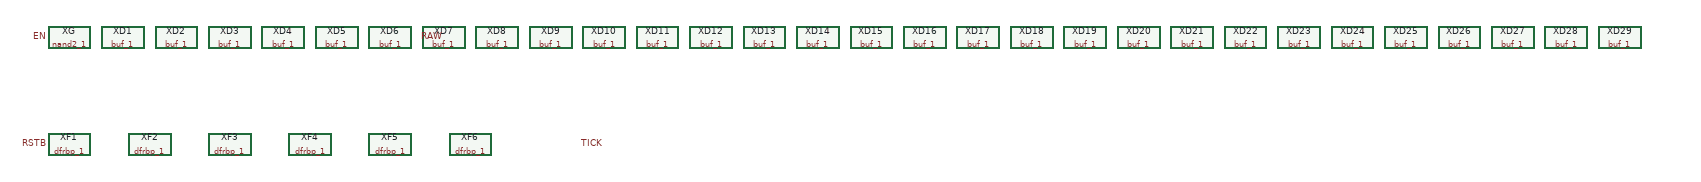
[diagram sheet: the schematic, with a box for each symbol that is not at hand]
v {xschem version=3.4.7 file_version=1.2
* watchdog ring + divider (generated)
}
G {}
K {}
V {}
S {}
E {}
C {sky130_stdcells/nand2_1.sym} 0 0 0 0 {name=XG VGND=GND VNB=GND VPB=VDD VPWR=VDD prefix=sky130_fd_sc_hd__}
C {sky130_stdcells/buf_1.sym} 100 0 0 0 {name=XD1 VGND=GND VNB=GND VPB=VDD VPWR=VDD prefix=sky130_fd_sc_hd__}
C {sky130_stdcells/buf_1.sym} 200 0 0 0 {name=XD2 VGND=GND VNB=GND VPB=VDD VPWR=VDD prefix=sky130_fd_sc_hd__}
C {sky130_stdcells/buf_1.sym} 300 0 0 0 {name=XD3 VGND=GND VNB=GND VPB=VDD VPWR=VDD prefix=sky130_fd_sc_hd__}
C {sky130_stdcells/buf_1.sym} 400 0 0 0 {name=XD4 VGND=GND VNB=GND VPB=VDD VPWR=VDD prefix=sky130_fd_sc_hd__}
C {sky130_stdcells/buf_1.sym} 500 0 0 0 {name=XD5 VGND=GND VNB=GND VPB=VDD VPWR=VDD prefix=sky130_fd_sc_hd__}
C {sky130_stdcells/buf_1.sym} 600 0 0 0 {name=XD6 VGND=GND VNB=GND VPB=VDD VPWR=VDD prefix=sky130_fd_sc_hd__}
C {sky130_stdcells/buf_1.sym} 700 0 0 0 {name=XD7 VGND=GND VNB=GND VPB=VDD VPWR=VDD prefix=sky130_fd_sc_hd__}
C {sky130_stdcells/buf_1.sym} 800 0 0 0 {name=XD8 VGND=GND VNB=GND VPB=VDD VPWR=VDD prefix=sky130_fd_sc_hd__}
C {sky130_stdcells/buf_1.sym} 900 0 0 0 {name=XD9 VGND=GND VNB=GND VPB=VDD VPWR=VDD prefix=sky130_fd_sc_hd__}
C {sky130_stdcells/buf_1.sym} 1000 0 0 0 {name=XD10 VGND=GND VNB=GND VPB=VDD VPWR=VDD prefix=sky130_fd_sc_hd__}
C {sky130_stdcells/buf_1.sym} 1100 0 0 0 {name=XD11 VGND=GND VNB=GND VPB=VDD VPWR=VDD prefix=sky130_fd_sc_hd__}
C {sky130_stdcells/buf_1.sym} 1200 0 0 0 {name=XD12 VGND=GND VNB=GND VPB=VDD VPWR=VDD prefix=sky130_fd_sc_hd__}
C {sky130_stdcells/buf_1.sym} 1300 0 0 0 {name=XD13 VGND=GND VNB=GND VPB=VDD VPWR=VDD prefix=sky130_fd_sc_hd__}
C {sky130_stdcells/buf_1.sym} 1400 0 0 0 {name=XD14 VGND=GND VNB=GND VPB=VDD VPWR=VDD prefix=sky130_fd_sc_hd__}
C {sky130_stdcells/buf_1.sym} 1500 0 0 0 {name=XD15 VGND=GND VNB=GND VPB=VDD VPWR=VDD prefix=sky130_fd_sc_hd__}
C {sky130_stdcells/buf_1.sym} 1600 0 0 0 {name=XD16 VGND=GND VNB=GND VPB=VDD VPWR=VDD prefix=sky130_fd_sc_hd__}
C {sky130_stdcells/buf_1.sym} 1700 0 0 0 {name=XD17 VGND=GND VNB=GND VPB=VDD VPWR=VDD prefix=sky130_fd_sc_hd__}
C {sky130_stdcells/buf_1.sym} 1800 0 0 0 {name=XD18 VGND=GND VNB=GND VPB=VDD VPWR=VDD prefix=sky130_fd_sc_hd__}
C {sky130_stdcells/buf_1.sym} 1900 0 0 0 {name=XD19 VGND=GND VNB=GND VPB=VDD VPWR=VDD prefix=sky130_fd_sc_hd__}
C {sky130_stdcells/buf_1.sym} 2000 0 0 0 {name=XD20 VGND=GND VNB=GND VPB=VDD VPWR=VDD prefix=sky130_fd_sc_hd__}
C {sky130_stdcells/buf_1.sym} 2100 0 0 0 {name=XD21 VGND=GND VNB=GND VPB=VDD VPWR=VDD prefix=sky130_fd_sc_hd__}
C {sky130_stdcells/buf_1.sym} 2200 0 0 0 {name=XD22 VGND=GND VNB=GND VPB=VDD VPWR=VDD prefix=sky130_fd_sc_hd__}
C {sky130_stdcells/buf_1.sym} 2300 0 0 0 {name=XD23 VGND=GND VNB=GND VPB=VDD VPWR=VDD prefix=sky130_fd_sc_hd__}
C {sky130_stdcells/buf_1.sym} 2400 0 0 0 {name=XD24 VGND=GND VNB=GND VPB=VDD VPWR=VDD prefix=sky130_fd_sc_hd__}
C {sky130_stdcells/buf_1.sym} 2500 0 0 0 {name=XD25 VGND=GND VNB=GND VPB=VDD VPWR=VDD prefix=sky130_fd_sc_hd__}
C {sky130_stdcells/buf_1.sym} 2600 0 0 0 {name=XD26 VGND=GND VNB=GND VPB=VDD VPWR=VDD prefix=sky130_fd_sc_hd__}
C {sky130_stdcells/buf_1.sym} 2700 0 0 0 {name=XD27 VGND=GND VNB=GND VPB=VDD VPWR=VDD prefix=sky130_fd_sc_hd__}
C {sky130_stdcells/buf_1.sym} 2800 0 0 0 {name=XD28 VGND=GND VNB=GND VPB=VDD VPWR=VDD prefix=sky130_fd_sc_hd__}
C {sky130_stdcells/buf_1.sym} 2900 0 0 0 {name=XD29 VGND=GND VNB=GND VPB=VDD VPWR=VDD prefix=sky130_fd_sc_hd__}
C {sky130_stdcells/dfrbp_1.sym} 0 200 0 0 {name=XF1 VGND=GND VNB=GND VPB=VDD VPWR=VDD prefix=sky130_fd_sc_hd__}
C {sky130_stdcells/dfrbp_1.sym} 150 200 0 0 {name=XF2 VGND=GND VNB=GND VPB=VDD VPWR=VDD prefix=sky130_fd_sc_hd__}
C {sky130_stdcells/dfrbp_1.sym} 300 200 0 0 {name=XF3 VGND=GND VNB=GND VPB=VDD VPWR=VDD prefix=sky130_fd_sc_hd__}
C {sky130_stdcells/dfrbp_1.sym} 450 200 0 0 {name=XF4 VGND=GND VNB=GND VPB=VDD VPWR=VDD prefix=sky130_fd_sc_hd__}
C {sky130_stdcells/dfrbp_1.sym} 600 200 0 0 {name=XF5 VGND=GND VNB=GND VPB=VDD VPWR=VDD prefix=sky130_fd_sc_hd__}
C {sky130_stdcells/dfrbp_1.sym} 750 200 0 0 {name=XF6 VGND=GND VNB=GND VPB=VDD VPWR=VDD prefix=sky130_fd_sc_hd__}
C {devices/lab_pin.sym} -40 0 0 0 {name=p0 lab=EN}
C {devices/lab_pin.sym} -40 200 0 0 {name=p1 lab=RSTB}
C {devices/lab_pin.sym} 700 0 0 0 {name=p2 lab=RAW}
C {devices/lab_pin.sym} 1000 200 0 0 {name=p3 lab=TICK}
